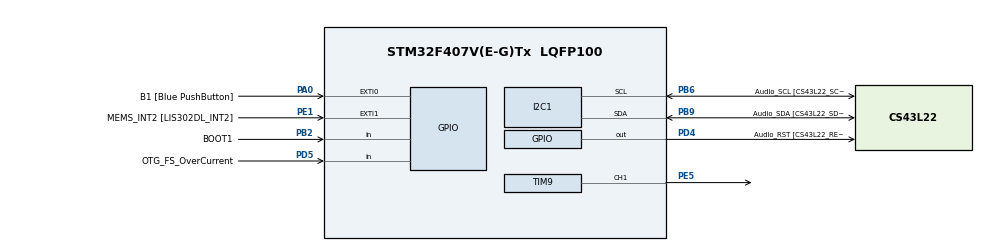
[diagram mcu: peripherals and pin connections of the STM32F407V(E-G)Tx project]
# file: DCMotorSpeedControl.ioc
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Mcu.Family=STM32F4
Mcu.Name=STM32F407V(E-G)Tx
Mcu.Package=LQFP100
NVIC.PriorityGroup=NVIC_PRIORITYGROUP_0
PA0-WKUP.GPIO_Label=B1 [Blue PushButton]
PA0-WKUP.GPIO_ModeDefaultEXTI=GPIO_MODE_EVT_RISING
PA0-WKUP.GPIO_PuPd=GPIO_NOPULL
PA0-WKUP.Signal=GPXTI0
PA13.GPIO_Label=SWDIO
PA13.Mode=Serial_Wire
PA13.Signal=SYS_JTMS-SWDIO
PA14.GPIO_Label=SWCLK
PA14.Mode=Serial_Wire
PA14.Signal=SYS_JTCK-SWCLK
PB2.GPIO_Label=BOOT1
PB2.GPIO_Mode=GPIO_MODE_INPUT
PB2.GPIO_PuPd=GPIO_NOPULL
PB2.Signal=GPIO_Input
PB3.GPIO_Label=SWO
PB3.Signal=SYS_JTDO-SWO
PB6.GPIO_Label=Audio_SCL [CS43L22_SCL]
PB6.GPIO_Mode=GPIO_MODE_AF_OD
PB6.GPIO_Pu=GPIO_PULLUP
PB6.GPIO_PuPd=GPIO_NOPULL
PB6.GPIO_Speed=GPIO_SPEED_FREQ_LOW
PB6.Mode=I2C
PB6.Signal=I2C1_SCL
PB9.GPIO_Label=Audio_SDA [CS43L22_SDA]
PB9.GPIO_Mode=GPIO_MODE_AF_OD
PB9.GPIO_Pu=GPIO_PULLUP
PB9.GPIO_PuPd=GPIO_NOPULL
PB9.GPIO_Speed=GPIO_SPEED_FREQ_LOW
PB9.Mode=I2C
PB9.Signal=I2C1_SDA
PC10.GPIO_Label=I2S3_SCK [CS43L22_SCLK]
PC10.GPIO_Mode=GPIO_MODE_AF_PP
PC10.GPIO_PuPd=GPIO_NOPULL
PC10.GPIO_Speed=GPIO_SPEED_FREQ_LOW
PC10.Signal=I2S3_CK
PC12.GPIO_Label=I2S3_SD [CS43L22_SDIN]
PC12.GPIO_Mode=GPIO_MODE_AF_PP
PC12.GPIO_PuPd=GPIO_NOPULL
PC12.GPIO_Speed=GPIO_SPEED_FREQ_LOW
PC12.Signal=I2S3_SD
PC14-OSC32_IN.GPIO_Label=PC14-OSC32_IN
PC14-OSC32_IN.Mode=LSE-External-Oscillator
PC14-OSC32_IN.Signal=RCC_OSC32_IN
PC15-OSC32_OUT.GPIO_Label=PC15-OSC32_OUT
PC15-OSC32_OUT.Mode=LSE-External-Oscillator
PC15-OSC32_OUT.Signal=RCC_OSC32_OUT
PD4.GPIO_Label=Audio_RST [CS43L22_RESET]
PD4.GPIO_PuPd=GPIO_NOPULL
PD4.GPIO_Speed=GPIO_SPEED_FREQ_LOW
PD4.Signal=GPIO_Output
PD5.GPIO_Label=OTG_FS_OverCurrent
PD5.GPIO_Mode=GPIO_MODE_INPUT
PD5.GPIO_PuPd=GPIO_NOPULL
PD5.Signal=GPIO_Input
PE1.GPIO_Label=MEMS_INT2 [LIS302DL_INT2]
PE1.GPIO_ModeDefaultEXTI=GPIO_MODE_EVT_RISING
PE1.GPIO_PuPd=GPIO_NOPULL
PE1.Signal=GPXTI1
PE5.Signal=S_TIM9_CH1
PH0-OSC_IN.GPIO_Label=PH0-OSC_IN
PH0-OSC_IN.Mode=HSE-External-Oscillator
PH0-OSC_IN.Signal=RCC_OSC_IN
PH1-OSC_OUT.GPIO_Label=PH1-OSC_OUT
PH1-OSC_OUT.Mode=HSE-External-Oscillator
PH1-OSC_OUT.Signal=RCC_OSC_OUT
ProjectManager.HeapSize=0x200
ProjectManager.StackSize=0x400
ProjectManager.TargetToolchain=STM32CubeIDE
RCC.48MHZClocksFreq_Value=22857142.85714286
RCC.AHBFreq_Value=80000000
RCC.APB1CLKDivider=RCC_HCLK_DIV2
RCC.APB1Freq_Value=40000000
RCC.APB1TimFreq_Value=80000000
RCC.APB2CLKDivider=RCC_HCLK_DIV2
RCC.APB2Freq_Value=40000000
RCC.APB2TimFreq_Value=80000000
RCC.CortexFreq_Value=80000000
RCC.HCLKFreq_Value=80000000
RCC.HSE_VALUE=8000000
RCC.HSI_VALUE=16000000
RCC.PLLM=8
RCC.PLLN=80
RCC.PLLQ=7
RCC.SYSCLKFreq_VALUE=80000000
RCC.SYSCLKSource=RCC_SYSCLKSOURCE_PLLCLK
RCC.VCOOutputFreq_Value=160000000
SH.S_TIM9_CH1.0=TIM9_CH1,PWM Generation1 CH1
TIM9.Channel-PWM\ Generation1\ CH1=TIM_CHANNEL_1
VP_TIM9_VS_ClockSourceINT.Mode=Internal
board=STM32F407G-DISC1

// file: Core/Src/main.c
/* USER CODE BEGIN Header */
/**
  ******************************************************************************
  * @file           : main.c
  * @brief          : Main program body
  ******************************************************************************
  * @attention
  *
  * Copyright (c) 2024 STMicroelectronics.
  * All rights reserved.
  *
  * This software is licensed under terms that can be found in the LICENSE file
  * in the root directory of this software component.
  * If no LICENSE file comes with this software, it is provided AS-IS.
  *
  ******************************************************************************
  */
/* USER CODE END Header */
#include "main.h"
#include <string.h>

I2C_HandleTypeDef hi2c1;

TIM_HandleTypeDef htim9;

void SystemClock_Config(void);
static void MX_GPIO_Init(void);
static void MX_I2C1_Init(void);
static void MX_TIM9_Init(void);
static void SpinDCMotor(void);
static void StartDCMotor(void);
//static void Error_Handler(void);
/* USER CODE BEGIN PFP */
GPIO_InitTypeDef ForDirPE3;
GPIO_InitTypeDef RevDirPE1;
GPIO_InitTypeDef MotorSpeedControlPE5;
uint8_t was_button_pressed = FALSE;
uint8_t button_press_count = 0;

/* USER CODE END PFP */

int main(void)
{

  /* MCU Configuration--------------------------------------------------------*/

  /* Reset of all peripherals, Initializes the Flash interface and the Systick. */
  HAL_Init();

  /* Configure the system clock */
  SystemClock_Config();

  /* Initialize all configured peripherals */
  MX_GPIO_Init();
  MX_I2C1_Init();
  MX_TIM9_Init();
  HAL_TIM_PWM_Start(&htim9, TIM_CHANNEL_1);

  /* Infinite loop */
  /* USER CODE BEGIN WHILE */
  while (1)
  {
//	  if ((! (HAL_GPIO_ReadPin(GPIOB, GPIO_PIN_9)) || was_button_pressed) && ! button_press_count)
//	  	{
//	  		was_button_pressed = TRUE;
//	  		button_press_count = 1;
//	  	}else if (HAL_GPIO_ReadPin(GPIOB, GPIO_PIN_9) && (button_press_count == 1))
//	  	{
//	  		was_button_pressed = TRUE;
//	  		button_press_count = 1;
//	  	}else if (! HAL_GPIO_ReadPin(GPIOB, GPIO_PIN_9) && (button_press_count == 1))
//	  	{
//	  		was_button_pressed = TRUE;
//	  		button_press_count = 2;
//	  	}
//
//	  	if(was_button_pressed && (button_press_count == 1) )
//	  	{
//	  		HAL_GPIO_WritePin(GPIOE, GPIO_PIN_3, SET);
//			HAL_GPIO_WritePin(GPIOE, GPIO_PIN_1, RESET);
//			__HAL_TIM_SET_COMPARE(&htim9,TIM_CHANNEL_1,800);
//	  	}
//	  	else if(was_button_pressed && (button_press_count == 2) )
//	  	{
//	  		__HAL_TIM_SET_COMPARE(&htim9,TIM_CHANNEL_1,0);
//	  	}
    /* USER CODE END WHILE */

  }
}

void SystemClock_Config(void)
{
  RCC_OscInitTypeDef RCC_OscInitStruct = {0};
  RCC_ClkInitTypeDef RCC_ClkInitStruct = {0};

  /** Configure the main internal regulator output voltage
  */
  __HAL_RCC_PWR_CLK_ENABLE();
  __HAL_PWR_VOLTAGESCALING_CONFIG(PWR_REGULATOR_VOLTAGE_SCALE1);
  /** Initializes the RCC Oscillators according to the specified parameters
  * in the RCC_OscInitTypeDef structure.
  */
  RCC_OscInitStruct.OscillatorType = RCC_OSCILLATORTYPE_HSI;
  RCC_OscInitStruct.HSIState = RCC_HSI_ON;
  RCC_OscInitStruct.HSICalibrationValue = RCC_HSICALIBRATION_DEFAULT;
  RCC_OscInitStruct.PLL.PLLState = RCC_PLL_ON;
  RCC_OscInitStruct.PLL.PLLSource = RCC_PLLSOURCE_HSI;
  RCC_OscInitStruct.PLL.PLLM = 16;
  RCC_OscInitStruct.PLL.PLLN = 100;
  RCC_OscInitStruct.PLL.PLLP = RCC_PLLP_DIV2;
  RCC_OscInitStruct.PLL.PLLQ = 5;
  if (HAL_RCC_OscConfig(&RCC_OscInitStruct) != HAL_OK)
  {
    Error_Handler();
  }
  /** Initializes the CPU, AHB and APB buses clocks
  */
  RCC_ClkInitStruct.ClockType = RCC_CLOCKTYPE_HCLK|RCC_CLOCKTYPE_SYSCLK
                              |RCC_CLOCKTYPE_PCLK1|RCC_CLOCKTYPE_PCLK2;
  RCC_ClkInitStruct.SYSCLKSource = RCC_SYSCLKSOURCE_PLLCLK;
  RCC_ClkInitStruct.AHBCLKDivider = RCC_SYSCLK_DIV1;
  RCC_ClkInitStruct.APB1CLKDivider = RCC_HCLK_DIV2;
  RCC_ClkInitStruct.APB2CLKDivider = RCC_HCLK_DIV2;

  if (HAL_RCC_ClockConfig(&RCC_ClkInitStruct, FLASH_LATENCY_2) != HAL_OK)
  {
    Error_Handler();
  }
}

static void MX_I2C1_Init(void)
{

  hi2c1.Instance = I2C1;
  hi2c1.Init.ClockSpeed = 100000;
  hi2c1.Init.DutyCycle = I2C_DUTYCYCLE_2;
  hi2c1.Init.OwnAddress1 = 0;
  hi2c1.Init.AddressingMode = I2C_ADDRESSINGMODE_7BIT;
  hi2c1.Init.DualAddressMode = I2C_DUALADDRESS_DISABLE;
  hi2c1.Init.OwnAddress2 = 0;
  hi2c1.Init.GeneralCallMode = I2C_GENERALCALL_DISABLE;
  hi2c1.Init.NoStretchMode = I2C_NOSTRETCH_DISABLE;
  if (HAL_I2C_Init(&hi2c1) != HAL_OK)
  {
    Error_Handler();
  }

}
/*
 * Code to start the DC Motor when a button press is detected
 */
//static void StartDCMotor(void)
//{
//
//	if ((! (HAL_GPIO_ReadPin(GPIOB, GPIO_PIN_9)) || was_button_pressed) && ! button_press_count)
//	{
//		was_button_pressed = TRUE;
//		button_press_count = 1;
//	}else if (HAL_GPIO_ReadPin(GPIOB, GPIO_PIN_9) && (button_press_count == 1))
//	{
//		was_button_pressed = TRUE;
//		button_press_count = 1;
//	}else if (! HAL_GPIO_ReadPin(GPIOB, GPIO_PIN_9) && (button_press_count == 1))
//	{
//		was_button_pressed = TRUE;
//		button_press_count = 2;
//	}
//
//	if(was_button_pressed && (button_press_count == 1) )
//	{
//		SpinDCMotor();
//	}
//	else if(was_button_pressed && (button_press_count == 2) )
//	{
////		HAL_GPIO_WritePin(GPIOE, GPIO_PIN_3, SET);
////		HAL_GPIO_WritePin(GPIOE, GPIO_PIN_1, RESET);
//	//	TIM9->CCR1 = 50000;
//		__HAL_TIM_SET_COMPARE(&htim9,TIM_CHANNEL_1,0);
//	}
//}
/*
 * Code to start the DC Motor
 */
//static void SpinDCMotor(void)
//{
//	HAL_GPIO_WritePin(GPIOE, GPIO_PIN_3, SET);
//	HAL_GPIO_WritePin(GPIOE, GPIO_PIN_1, RESET);
////	TIM9->CCR1 = 50000;
//	__HAL_TIM_SET_COMPARE(&htim9,TIM_CHANNEL_1,800);
//
//}

static void MX_TIM9_Init(void)
{

	TIM_OC_InitTypeDef timer9_PWM_config;
	memset(&timer9_PWM_config,0,sizeof(timer9_PWM_config));
	htim9.Instance = TIM9;
	htim9.Init.Period = 1000-1;
	htim9.Init.Prescaler = 49;
	if ( HAL_TIM_PWM_Init(&htim9) != HAL_OK)
	{
		Error_Handler();
	}

	timer9_PWM_config.OCMode = TIM_OCMODE_PWM1;
	timer9_PWM_config.OCNPolarity = TIM_OCNPOLARITY_HIGH;
	timer9_PWM_config.Pulse = 0;
	HAL_TIM_PWM_ConfigChannel(&htim9, &timer9_PWM_config, TIM_CHANNEL_1);

}

#define IRQ_NO_EXTI9_5					23
#define NVIC_IRQ_PRI15					15
static void MX_GPIO_Init(void)
{
	GPIO_InitTypeDef ForDirPE3 = {0};
	GPIO_InitTypeDef RevDirPE1 = {0};
	GPIO_InitTypeDef StartButton = {0};

	// Enable the clock for the GPIOE peripheral
	__HAL_RCC_GPIOE_CLK_ENABLE();
	// Enable the clock for the GPIOB peripheral
	__HAL_RCC_GPIOB_CLK_ENABLE();

	// GPIO Initialization for forward direction
	ForDirPE3.Mode = GPIO_MODE_OUTPUT_PP;
	ForDirPE3.Pin = GPIO_PIN_3;
	ForDirPE3.Pull = GPIO_NOPULL;
	HAL_GPIO_Init(GPIOE, &ForDirPE3);

	// GPIO Initialization for reverse direction
	RevDirPE1.Mode = GPIO_MODE_OUTPUT_PP;
	RevDirPE1.Pin = GPIO_PIN_1;
	RevDirPE1.Pull = GPIO_NOPULL;
	HAL_GPIO_Init(GPIOE, &RevDirPE1);

	// GPIO Initialization for starting the DC Motor
	StartButton.Pin = GPIO_PIN_9;
	StartButton.Mode = GPIO_MODE_IT_FALLING;
	StartButton.Pull = GPIO_NOPULL;
	HAL_GPIO_Init(GPIOB, &StartButton);

	GPIO_IRQPriorityConfig(IRQ_NO_EXTI9_5,NVIC_IRQ_PRI15);
	//IRQ configurations
	GPIO_IRQInterruptConfig(IRQ_NO_EXTI9_5,ENABLE);

}
void delay(void)
{
	for (uint32_t i=0;i<=500000/2;i++);
}
void EXTI9_5_IRQHandler(void)
{
	delay();
	uint16_t Speed = 900;
	HAL_GPIO_EXTI_IRQHandler(GPIO_PIN_9);
	if (button_press_count == 0)
	{
		HAL_GPIO_WritePin(GPIOE, GPIO_PIN_3, SET);
		HAL_GPIO_WritePin(GPIOE, GPIO_PIN_1, RESET);
		__HAL_TIM_SET_COMPARE(&htim9,TIM_CHANNEL_1,Speed);
		button_press_count = 1;

	}else if(button_press_count == 1)
	{
		__HAL_TIM_SET_COMPARE(&htim9,TIM_CHANNEL_1,0);
		button_press_count = 0;
	}

}

void Error_Handler(void)
{
  __disable_irq();
  while (1)
  {
  }
}
